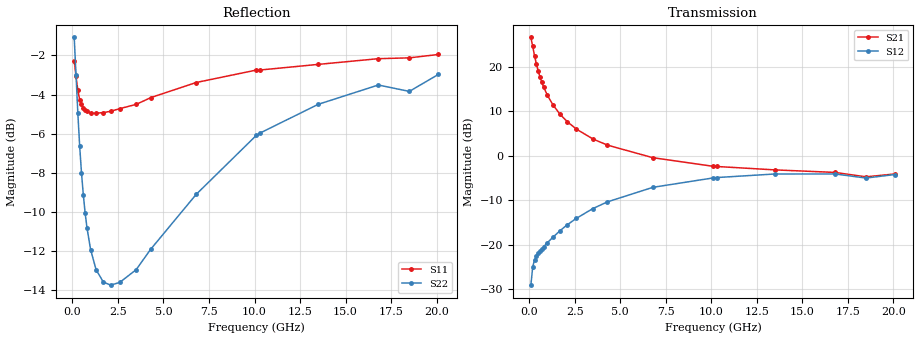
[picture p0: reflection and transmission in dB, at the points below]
!  Infineon Technologies AG
! BFR380L3 , PF131585-7, No.6, Th 09.10.01, soldered on pcb-board, measured with PP GSG850
!  Vce=0.75 V,  Ic=7.5 mA
! Common Emitter S-Parameters:  15. November 2001
#  GHz  S  MA  R  50
! f  S11  S21  S12  S22
! GHz  Mag  Ang  Mag  Ang  Mag  Ang  Mag  Ang
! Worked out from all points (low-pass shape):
!   201 points, 100 MHz to 20.1 GHz, reference 50 ohm
!   highest |S21| = 26.57 dB at 100 MHz (marker M1); lowest = -4.8 dB at 18.5 GHz (marker M2)
!   |S21| within 3 dB of the highest: start of sweep to 247.3 MHz
!   lowest |S11| = -5.0 dB at 1.3 GHz (marker M3), VSWR 3.59, Z = 13.9 - j1.66 ohm
!   |S11| at or under -10 dB: nowhere
!   |S22| runs from -13.8 to -1.1 dB; largest |S21 - S12| = 21
!   S11 on the Smith chart (normalised r, x): 100 MHz: 0.79, -2.13; 300 MHz: 0.33, -0.72; 1 GHz: 0.28, -0.12; 4.3 GHz: 0.28, +0.43; 10.3 GHz: 0.40, +1.21; 20.1 GHz: 0.94, +2.58
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0.1  0.7682 -45.6  21.29 152.3  0.03497 66.5  0.8836 -30.7
0.2  0.7028 -80.2  16.87 132.4  0.05553 54.2  0.7079 -53.3
0.3  0.6465 -104.4  13.3 119.6  0.06735 46.9  0.5652 -68.6
0.4  0.6124 -121.0  10.77 110.9  0.07427 43.8  0.4656 -79.8
0.5  0.5955 -133.3  8.964 104.5  0.07986 43.0  0.3978 -88.5
0.6  0.5813 -142.6  7.646 99.6  0.08495 42.9  0.3494 -95.6
0.7  0.5762 -150.1  6.663 95.5  0.08959 43.3  0.314 -101.8
0.8  0.571 -155.9  5.893 92.0  0.09448 44.2  0.288 -107.1
1  0.5663 -165.5  4.79 86.2  0.1044 45.9  0.2531 -116.1
1.3  0.5647 -175.9  3.745 79.1  0.1201 48.3  0.2248 -127.1
1.7  0.5674 173.4  2.913 71.1  0.1429 50.1  0.2089 -138.2
2.1  0.5715 164.7  2.4 64.1  0.1667 51.0  0.2052 -146.9
2.6  0.5807 155.4  1.983 56.2  0.1969 50.9  0.2085 -155.9
3.5  0.5952 141.1  1.539 43.5  0.2533 48.3  0.2247 -168.5
4.3  0.6195 130.3  1.31 34.0  0.3014 44.9  0.2535 -179.4
6.8  0.6773 102.2  0.9458 10.3  0.4394 29.6  0.3504 151.6
10.1  0.7288 76.7  0.7577 -8.9  0.5601 8.5  0.496 121.0
10.3  0.729 75.4  0.7537 -9.7  0.5658 7.4  0.5027 119.2
13.5  0.7536 59.4  0.69 -23.6  0.6206 -11.8  0.5956 94.4
16.8  0.7794 47.4  0.6463 -34.5  0.6212 -27.2  0.6674 74.2
18.5  0.7832 45.3  0.5766 -41.8  0.5587 -35.6  0.6427 69.1
20.1  0.799 38.3  0.6219 -45.2  0.6124 -40.4  0.7105 58.7
